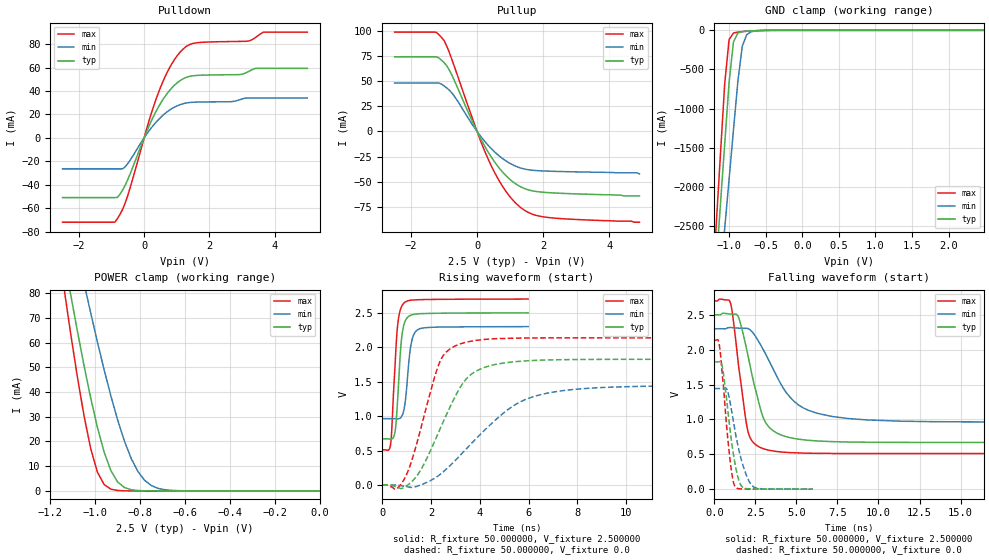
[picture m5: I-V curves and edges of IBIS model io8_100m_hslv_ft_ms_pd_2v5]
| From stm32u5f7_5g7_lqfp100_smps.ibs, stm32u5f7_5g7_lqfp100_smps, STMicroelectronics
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|   Model io8_100m_hslv_ft_ms_pd_2v5
[Model]  io8_100m_hslv_ft_ms_pd_2v5
Model_type I/O
Polarity   Non-Inverting
Enable   Active-Low
Vinl =   0.750000V
Vinh =   1.750000V
Vmeas =  1.250000V
Cref =   50.000000pF
Rref =   100.000000M
Vref =   0.0V
C_comp   3.340900pF   3.338500pF   3.380300pF
[Temperature Range]   25.000000   0.140000k   -40.000000
[Pullup Reference]   2.500000V   2.300000V   2.700000V
[Pulldown Reference]   0.0V   0.0V   0.0V
[POWER Clamp Reference]   2.500000V   2.300000V   2.700000V
[GND Clamp Reference]   0.0V   0.0V   0.0V
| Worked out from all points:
|   slope of the pulldown table from 0 to 0.375 V, typ, clamps not added: 16.1 ohm
|   slope of the pullup table from 0 to 0.375 V, typ, clamps not added: 16.6 ohm
|   GND clamp passes 1 mA (typ) near -0.50 V on its own axis
|   POWER clamp passes 1 mA (typ) near -0.86 V on its own axis
|   rising waveform, R_fixture 50.000000, V_fixture 2.500000: 20-80 % time 200ps typ, 226ps min, 206ps max; typ from 0.669 V to 2.5 V
|   rising waveform, R_fixture 50.000000, V_fixture 0.0: 20-80 % time 1.47ns typ, 2.6ns min, 1ns max; typ from 0 V to 1.82 V
|   falling waveform, R_fixture 50.000000, V_fixture 2.500000: 20-80 % time 1.12ns typ, 2.1ns min, 709ps max; typ from 2.5 V to 0.669 V
|   falling waveform, R_fixture 50.000000, V_fixture 0.0: 20-80 % time 605ps typ, 790ps min, 494ps max; typ from 1.82 V to 0 V
[Pulldown]
|Voltage   I(typ)   I(min)   I(max)
-2.5V     -51.01mA   -26.45mA   -72.04mA
-900mV    -51.01mA   -26.45mA   -72.04mA
-820mV    -50.89mA   -26.45mA   -69.09mA
-500mV    -35.59mA   -21.93mA   -49.09mA
140mV     9.489mA    5.639mA    13.76mA
460mV     27.5mA     16.24mA    40.22mA
860mV     43.07mA    25.18mA    63.88mA
1.26V     51.38mA    29.65mA    77.49mA
1.66V     53.45mA    30.63mA    81.42mA
3.18V     56.44mA    34.01mA    82.68mA
3.66V     59.44mA    34.01mA    90.42mA
5V        59.44mA    34.01mA    90.42mA
[Pullup]
|Voltage   I(typ)   I(min)   I(max)
-2.5V     74.05mA    48.12mA    98.57mA
-1.24V    74.05mA    48.12mA    98.43mA
-1V       68.25mA    45.17mA    90.14mA
-840mV    60.72mA    41mA       78.2mA
-680mV    49.98mA    34.51mA    63.59mA
-40mV     2.737mA    1.848mA    3.643mA
360mV     -21.77mA   -14.61mA   -29.22mA
840mV     -42.69mA   -28.49mA   -57.8mA
1.32V     -54.89mA   -36.24mA   -75.42mA
1.64V     -58.66mA   -38.36mA   -81.62mA
2.12V     -60.6mA    -39.32mA   -85.19mA
4.92V     -64mA      -42mA      -90mA
[GND_clamp]
|Voltage   I(typ)   I(min)   I(max)
-2.5V     -9.446A    -9.524A    -9.146A
-1.18V    -3.045A    -3.8A      -2.552A
-1.12V    -2.248A    -3.166A    -1.614A
-1.06V    -1.452A    -2.533A    -685.4mA
-1V       -665mA     -1.901A    -117.9mA
-940mV    -148mA     -1.272A    -34.34mA
-880mV    -35.14mA   -651.5mA   -22.8mA
-820mV    -16.02mA   -203.9mA   -17.08mA
-760mV    -10.47mA   -56.89mA   -12.28mA
-700mV    -7.079mA   -18.53mA   -8.16mA
-400mV    -112.4uA   -382.5uA   -53.84uA
2.48V     63.1uA     48.03uA    77.39uA
[POWER_clamp]
|Voltage   I(typ)   I(min)   I(max)
-2.49V    881mA      773.1mA    1.07A
-1.14V    95.25mA    122.7mA    82.82mA
-1.11V    79.9mA     109.7mA    64.14mA
-1.05V    50.87mA    84.26mA    30.57mA
-1.02V    37.63mA    72.04mA    17.17mA
-990mV    25.71mA    60.25mA    7.621mA
-930mV    8.217mA    38.43mA    713.9uA
-900mV    3.624mA    28.77mA    182.8uA
-840mV    490.7uA    13.24mA    11.35uA
-780mV    56.55uA    4.324mA    699nA
-660mV    716.5nA    226uA      9.775nA
0V        0A         19.49nA    0A
[Ramp]
| variable   typ   min   max
dV/dt_r  1.09464/1.47224n   0.86544/2.59711n   1.28148/1.00176n
dV/dt_f  1.09787/1.11768n   0.80201/2.10133n   1.31323/0.70756n
R_load = 50.000000
[Rising Waveform]
R_fixture= 50.000000
V_fixture= 2.500000
V_fixture_min= 2.300000
V_fixture_max= 2.700000
|time   V(typ)   V(min)   V(max)
0s        669.4mV    962.5mV    510.5mV
336.3ps   665.2mV    962.7mV    586.1mV
384.4ps   666.5mV    962.7mV    793.4mV
516.5ps   764.1mV    962mV      1.709V
648.6ps   1.37V      959.4mV    2.383V
756.8ps   2.007V     977.4mV    2.562V
876.9ps   2.317V     1.078V     2.638V
1.177ns   2.466V     2.042V     2.683V
1.453ns   2.484V     2.256V     2.689V
5.982ns   2.499V     2.299V     2.699V
[Rising Waveform]
R_fixture= 50.000000
V_fixture= 0.0
V_fixture_min= 0.0
V_fixture_max= 0.0
|time   V(typ)   V(min)   V(max)
0s        -92.04uV   -36.96uV   -134.1uV
700.7ps   -45.97mV   -5.893mV   -17.84mV
1.051ns   997.4uV    -28.46mV   199.5mV
1.351ns   102.5mV    -27.5mV    525.2mV
2.402ns   841.2mV    162.3mV    1.821V
3.403ns   1.523V     508.2mV    2.07V
4.154ns   1.702V     781.5mV    2.112V
5.506ns   1.791V     1.177V     2.132V
7.558ns   1.82V      1.376V     2.136V
24.92ns   1.825V     1.442V     2.136V
[Falling Waveform]
R_fixture= 50.000000
V_fixture= 2.500000
V_fixture_min= 2.300000
V_fixture_max= 2.700000
|time   V(typ)   V(min)   V(max)
0s        2.499V     2.299V     2.699V
951ps     2.511V     2.317V     2.687V
1.101ns   2.509V     2.315V     2.51V
1.451ns   2.473V     2.308V     1.809V
2.052ns   1.906V     2.302V     819.6mV
2.953ns   1.04V      2.009V     582.6mV
3.554ns   841.9mV    1.735V     548.2mV
4.855ns   726.7mV    1.258V     521.8mV
7.207ns   681.4mV    1.04V      512mV
24.92ns   669.4mV    962.5mV    510.5mV
[Falling Waveform]
R_fixture= 50.000000
V_fixture= 0.0
V_fixture_min= 0.0
V_fixture_max= 0.0
|time   V(typ)   V(min)   V(max)
0s        1.825V     1.442V     2.136V
264.3ps   1.825V     1.443V     2.106V
468.5ps   1.772V     1.442V     1.666V
732.7ps   1.305V     1.441V     933.8mV
936.9ps   876.9mV    1.266V     448.4mV
1.105ns   578.5mV    1.042V     158.1mV
1.261ns   356.6mV    828mV      36.29mV
1.646ns   45.64mV    418.3mV    3.681mV
2.342ns   3.026mV    40.96mV    1.457mV
5.982ns   -92.04uV   -36.96uV   -134.1uV
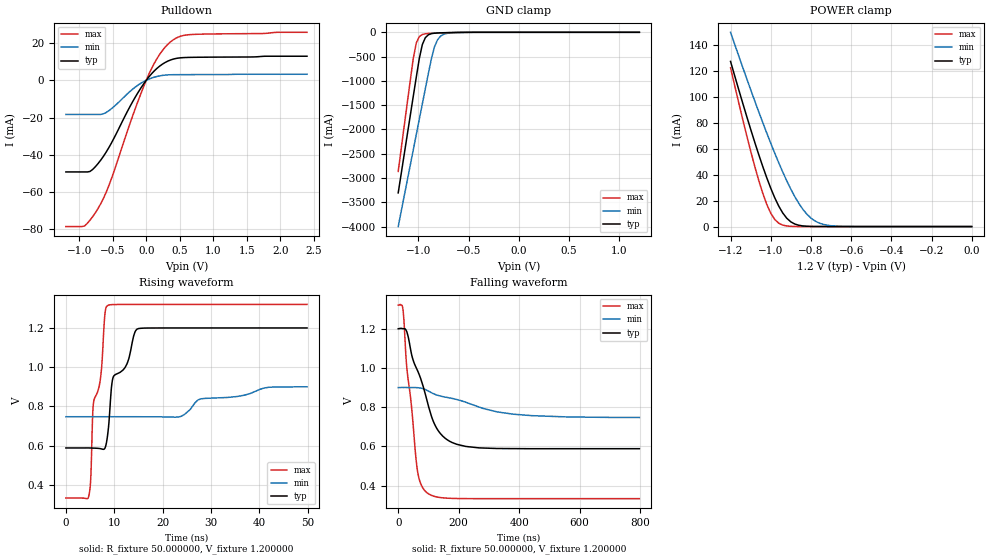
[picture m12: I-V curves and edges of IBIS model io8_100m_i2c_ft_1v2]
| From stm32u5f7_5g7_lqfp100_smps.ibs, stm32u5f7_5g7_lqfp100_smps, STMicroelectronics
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|   Model io8_100m_i2c_ft_1v2
[Model]  io8_100m_i2c_ft_1v2
Model_type I/O_open_drain
Polarity   Non-Inverting
Enable   Active-Low
Vinl =   0.360000V
Vinh =   0.840000V
Vmeas =  0.600000V
Cref =   50.000000pF
Rref =   100.000000M
Vref =   0.600000V
C_comp   2.954600pF   2.884400pF   3.002700pF
[Temperature Range]   25.000000   0.140000k   -40.000000
[Pullup Reference]   1.200000V   0.900000V   1.320000V
[Pulldown Reference]   0.0V   0.0V   0.0V
[POWER Clamp Reference]   1.200000V   0.900000V   1.320000V
[GND Clamp Reference]   0.0V   0.0V   0.0V
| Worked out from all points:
|   slope of the pulldown table from 0 to 0.18 V, typ, clamps not added: 25.7 ohm
|   GND clamp passes 1 mA (typ) near -0.51 V on its own axis
|   POWER clamp passes 1 mA (typ) near -0.86 V on its own axis
|   rising waveform, R_fixture 50.000000, V_fixture 1.200000: 20-80 % time 4.46ns typ, 13ns min, 2.41ns max; typ from 0.588 V to 1.2 V
|   falling waveform, R_fixture 50.000000, V_fixture 1.200000: 20-80 % time 78ns typ, 207ns min, 36ns max; typ from 1.2 V to 0.588 V
[Pulldown]
|Voltage   I(typ)   I(min)   I(max)
-1.2V     -49.24mA   -18.34mA   -78.57mA
-920mV    -49.24mA   -18.34mA   -78.21mA
-840mV    -48.98mA   -18.34mA   -75.14mA
-720mV    -44.76mA   -18.34mA   -68.87mA
-560mV    -36.26mA   -16.38mA   -56.73mA
-200mV    -11.29mA   -4.684mA   -18.8mA
0V        0A         0A         0A
160mV     6.399mA    2.052mA    11.64mA
360mV     10.86mA    2.957mA    20.57mA
480mV     11.93mA    3.021mA    23.25mA
640mV     12.29mA    3.041mA    24.48mA
2.4V      12.92mA    3.23mA     25.77mA
[GND_clamp]
|Voltage   I(typ)   I(min)   I(max)
-1.2V     -3.305A    -3.998A    -2.862A
-1.05V    -1.316A    -2.418A    -539.3mA
-1.02V    -921mA     -2.103A    -218.8mA
-990mV    -539.5mA   -1.788A    -87.43mA
-960mV    -252.1mA   -1.474A    -44.36mA
-930mV    -110.5mA   -1.16A     -30.32mA
-870mV    -28.03mA   -549.1mA   -21.09mA
-840mV    -18.43mA   -305.6mA   -18.27mA
-810mV    -13.9mA    -159.7mA   -15.73mA
-780mV    -11.23mA   -82.35mA   -13.37mA
-600mV    -2.976mA   -4.272mA   -3.058mA
1.2V      0A         14.74nA    0A
[POWER_clamp]
|Voltage   I(typ)   I(min)   I(max)
-1.2V     127mA      149.4mA    122.2mA
-1.12V    84.97mA    114mA      70.27mA
-1.06V    55.51mA    88.42mA    35.67mA
-1.02V    37.63mA    72.04mA    17.17mA
-1V       29.51mA    64.13mA    10.3mA
-960mV    15.69mA    48.99mA    2.571mA
-900mV    3.624mA    28.77mA    182.8uA
-840mV    490.7uA    13.24mA    11.35uA
-800mV    116.8uA    6.532mA    1.77uA
-740mV    13.2uA     1.723mA    109.1nA
-620mV    167.3nA    79.35uA    0A
0V        0A         17.84nA    0A
[Ramp]
| variable   typ   min   max
dV/dt_r  0.36680/4.44984n   91.35600m/13.03269n 0.59165/2.40549n
dV/dt_f  0.36692/77.96182n   91.27800m/0.20662u  0.59177/35.96252n
R_load = 50.000000
[Rising Waveform]
R_fixture= 50.000000
V_fixture= 1.200000
V_fixture_min= 0.900000
V_fixture_max= 1.320000
|time   V(typ)   V(min)   V(max)
0s        588.5mV    747.6mV    333.7mV
4.805ns   588.5mV    747.6mV    350.7mV
5.105ns   588.2mV    747.6mV    415.2mV
5.706ns   587.6mV    747.6mV    819.4mV
7.107ns   584.9mV    747.6mV    934.9mV
8.008ns   584.8mV    747.6mV    1.254V
8.509ns   633.1mV    747.6mV    1.312V
9.71ns    943.8mV    747.6mV    1.319V
14.71ns   1.194V     747.5mV    1.32V
49.85ns   1.2V       900mV      1.32V
[Falling Waveform]
R_fixture= 50.000000
V_fixture= 1.200000
V_fixture_min= 0.900000
V_fixture_max= 1.320000
|time   V(typ)   V(min)   V(max)
0s        1.2V       900mV      1.32V
16.02ns   1.2V       900.5mV    1.295V
28.83ns   1.183V     900.3mV    995.9mV
43.24ns   1.076V     900mV      814.2mV
64.06ns   986.1mV    899.4mV    472.7mV
94.49ns   838.3mV    886.2mV    364.8mV
139.3ns   666mV      856.9mV    339.4mV
222.6ns   600.3mV    825.8mV    334mV
382.8ns   588.9mV    764mV      333.7mV
797.6ns   588.5mV    747.6mV    333.7mV
